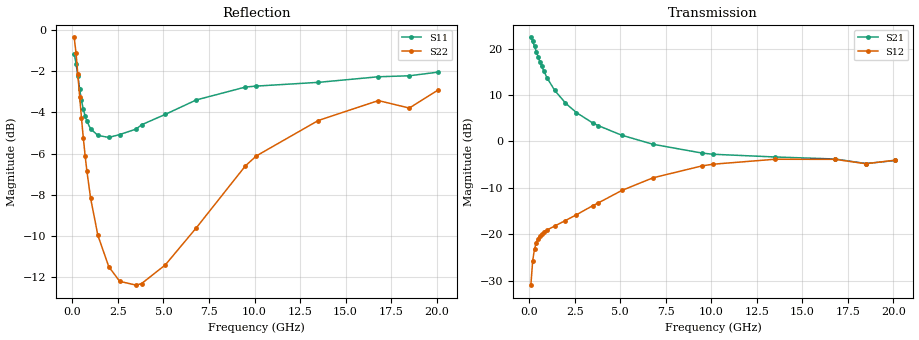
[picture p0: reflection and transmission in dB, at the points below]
!  Infineon Technologies AG
! BFR380L3 , PF131585-7, No.6, Th 09.10.01, soldered on pcb-board, measured with PP GSG850
!  Vce=3.0 V,  Ic=4.0 mA
! Common Emitter S-Parameters:  15. November 2001
#  GHz  S  MA  R  50
! f  S11  S21  S12  S22
! GHz  Mag  Ang  Mag  Ang  Mag  Ang  Mag  Ang
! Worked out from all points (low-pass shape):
!   201 points, 100 MHz to 20.1 GHz, reference 50 ohm
!   highest |S21| = 22.41 dB at 100 MHz (marker M1); lowest = -4.8 dB at 18.5 GHz (marker M2)
!   |S21| within 3 dB of the highest: start of sweep to 393.1 MHz
!   lowest |S11| = -5.2 dB at 2 GHz (marker M3), VSWR 3.43, Z = 14.6 - j0.387 ohm
!   |S11| at or under -10 dB: nowhere
!   |S22| runs from -12.5 to -0.3 dB; largest |S21 - S12| = 13
!   S11 on the Smith chart (normalised r, x): 100 MHz: 1.32, -4.16; 400 MHz: 0.36, -1.06; 1 GHz: 0.30, -0.33; 3.8 GHz: 0.28, +0.30; 9.5 GHz: 0.36, +1.09; 20.1 GHz: 0.99, +2.57
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0.1  0.8756 -24.7  13.2 163.2  0.02836 75.8  0.9615 -14.6
0.2  0.8304 -47.5  11.94 148.5  0.05222 65.4  0.8797 -27.2
0.3  0.774 -67.3  10.57 136.4  0.06953 56.6  0.7811 -37.1
0.4  0.7196 -83.5  9.262 126.6  0.0815 50.4  0.6892 -44.7
0.5  0.6751 -97.0  8.126 118.8  0.09004 46.1  0.611 -50.5
0.6  0.6433 -108.5  7.183 112.5  0.09632 43.3  0.5472 -54.8
0.7  0.6178 -118.2  6.417 107.0  0.101 41.2  0.4952 -58.2
0.8  0.6 -126.5  5.774 102.4  0.1051 39.9  0.4532 -61.0
1  0.5753 -139.9  4.795 94.8  0.1114 38.7  0.3903 -65.3
1.4  0.5548 -159.3  3.568 83.2  0.1227 39.3  0.3166 -71.7
2  0.5485 -179.0  2.587 69.9  0.1407 42.5  0.2655 -80.1
2.6  0.5575 166.6  2.046 59.0  0.1623 45.7  0.2446 -89.5
3.5  0.5747 149.2  1.58 45.1  0.2036 48.6  0.2395 -104.9
3.8  0.5889 144.6  1.48 41.2  0.2177 49.0  0.2416 -111.8
5.1  0.6242 125.6  1.165 25.5  0.297 46.7  0.2682 -136.9
6.8  0.6768 105.2  0.9327 10.4  0.4055 38.2  0.3301 -170.8
9.5  0.7276 81.5  0.7495 -4.7  0.5455 19.2  0.4676 148.0
10.1  0.7316 77.2  0.7279 -7.1  0.5685 14.9  0.4944 139.8
13.5  0.7471 58.8  0.6803 -20.6  0.6429 -8.4  0.6031 104.1
16.8  0.7709 47.2  0.6472 -32.2  0.6417 -25.4  0.6745 79.6
18.5  0.7752 45.2  0.578 -39.5  0.5752 -34.1  0.6468 73.3
20.1  0.7914 38.0  0.6235 -43.6  0.6284 -39.3  0.7166 62.2
